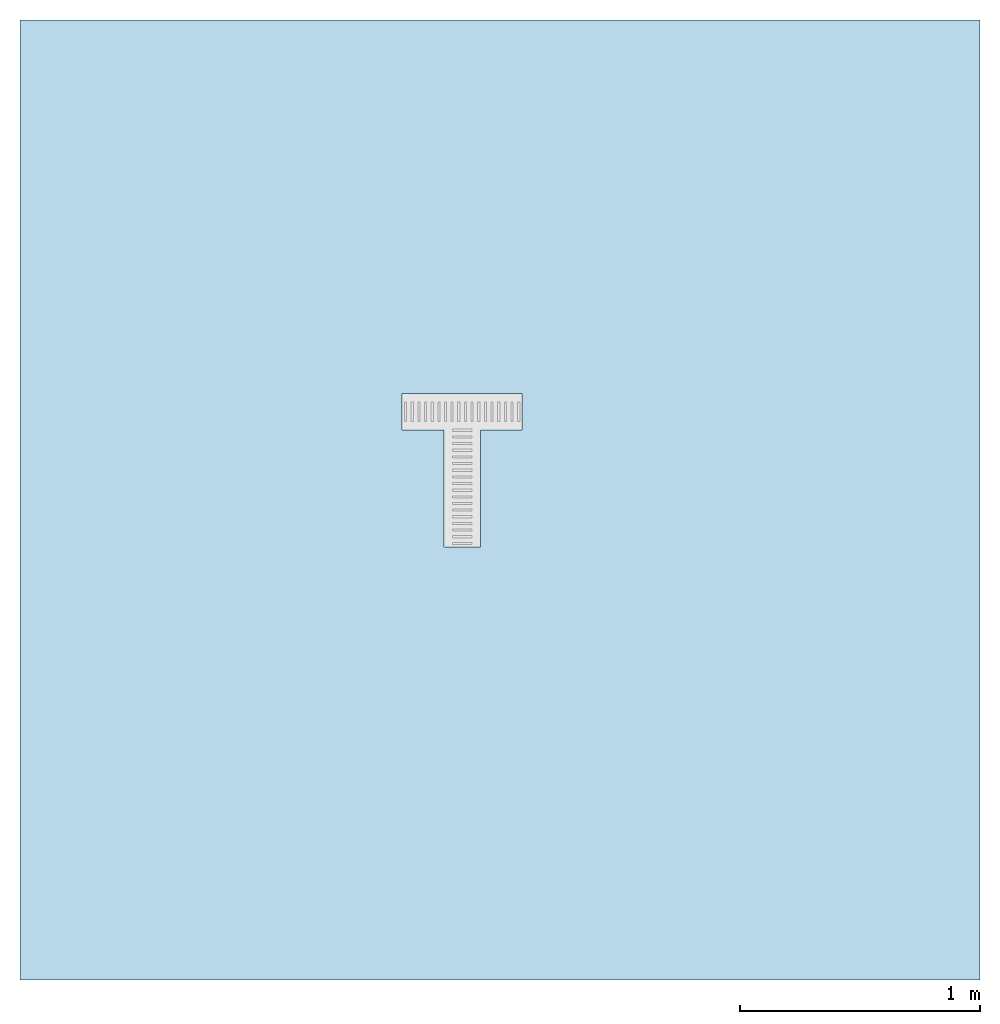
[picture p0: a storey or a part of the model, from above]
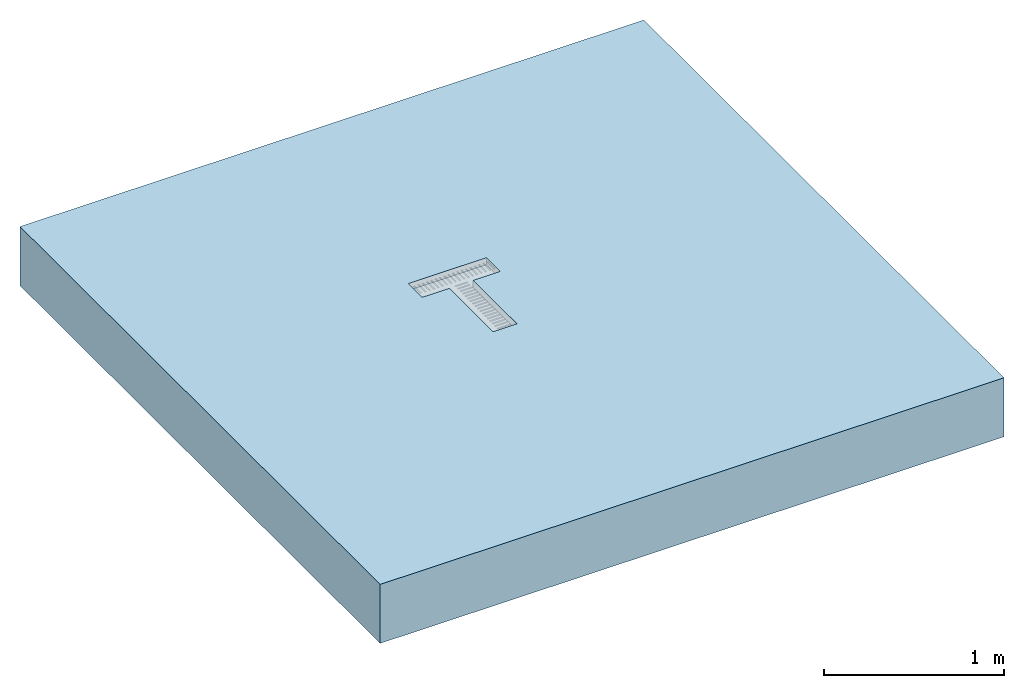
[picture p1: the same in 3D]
Properties of the parts of a building model (IFC2X3)

# File
Description: ViewDefinition [CoordinationView]
File name: 105261 - Level Invert Branch Unit.ifc
Time: 2014-03-20T14:31:36
Written by: Autodesk Revit 2013
Made in: 20120221_2030(x64)

# IfcProject, Project Number
LongName: Project Name; Phase: Project Status

# IfcSite, Default
RefLatitude: 42, 21, 30, 344238; RefLongitude: -71, -3, -35, -194702; RefElevation: 0 mm

# IfcBuilding
Pset_BuildingCommon - NumberOfStoreys: 1
Other - Project Issue Date: Issue Date; Project Name: Project Name; Client Name: Owner; Project Address: ## Street City, State Zip; Project Status: Project Status; Project Number: Project Number

# IfcBuildingStorey, Level 1
LongName: Level 1; Elevation: 0 mm
Constraints - Elevation Base: 0; Elevation: 0 mm
Graphics - Color: 0; Line Weight: 1; Symbol: M_Level Head - Circle: M_Level Head - Circle; Symbol at End 1 Default: no; Symbol at End 2 Default: yes; Line Pattern: Center
Identity Data - Building Story: yes; Structural: no; Name: Level 1
Dimensions - Computation Height: 0 mm

# IfcBuildingElementProxy: 105261 - Level Invert Branch Unit, ACO BD Deckline 125 Branch Unit:105261 - Level Invert Branch Unit:105261 - Level Invert Branch Unit:215225
In: Level 1
Material: Steel, Galvanized
Phasing - Phase Created: New Construction
Construction - End Plate Invert Flange: no; 105509 - C250 Perforated Grating - 500mm Long - Galvanized Finish.: no; 105523 - A15 Slotted Grating - 500mm Long - Galvanized Finish.: no; 15704 - C250 Composite Grating - 500mm Long - Black Coloured Finish.: no; End Plate Invert Web 2: no; 105525 - C250 Slotted Grating - 500mm Long - Galvanized Finish.: no; 10735 - C250 Composite Grating - 500mm Long - White Coloured Finish.: no; End Plate Invert Web 1: no; Grating: yes
Dimensions - Volume: 2593238 mm3
Constraints - Level: Level: Level 1; Moves With Nearby Elements: no
Pset_BuildingElementProxyCommon - Reference: 105261 - Level Invert Branch Unit
General - Product Description: ACO Deckline Level Invert Channel Branch; Product Code: 105261; Seal Colour: Black; Channel Recycled Material Content: 25 - 30 %; Seal Recyclable: Fully recyclable; Channel Colour: Galvanized; Product Range: ACO Deckline 125; Product Type: shallow invert surface water drainage system; Price: POA - contact ACO; Channel Material: Hot Dipped Galvanised Steel; Load Class: A15 - C250; Installation guidelines: X:\Electronic Literature\Building Drainage Literature\Deckline\Deckline 125.PDF; Weight (Kg): 3.9; Product Standard: BS EN 1433:2002, CE marked; NBS Specification: NBS Section Q10 Kerbs/edgings/channels/paving accessories, Clause 180 Drainage Channel Systems; Channel Recyclable: Fully recyclable; Maintenance guidelines: X:\Electronic Literature\Building Drainage Literature\Deckline\Deckline 125.PDF; Seal Material: Neoprene; Seal Recycled Material Content: 0%; Dimensions (LxWxH): 500 / 639mm x 153mm x 63mm
Identity Data - Cost: 0; Fax: +44 (0)1462 851490; Watermarked With: BIM Manager Premium Suite.; Watermarked By: www.acobd.com; Website: www.acobd.com; Manufacturer: ACO Building Drainage; Watermark2: This file is water marked and users are prohibited to reproduce, adapt, distribute this information.; E-mail Technical: abdtechnical@aco.co.uk; Address: ACO Business Centre, Caxton Road, Bedford, MK41 0LF; Telephone: +44 (0)1462 816666; Watermark1: This file is the property of ACO Technologies PLC; E-mail Sales: abdcommercial@aco.co.uk
Model Properties - Grating Product Code 15704: Load Class C250 - Composite Black - 500mm long - 1.2kg; Grating Product Code 105509: Load Class C250 - Perforated Galvanized Steel - 500mm long - 2.3kg; Grating Product Code 10735: Load Class C250 - Composite White - 500mm long - 1.2kg; Grating Product Code 105523: Load Class A15 - Slotted Galvanized Steel - 500mm long - 1.0kg; Grating Product Code 105525: Load Class C250 - Slotted Galvanized Steel - 500mm long - 2.3kg

# IfcOpeningElement: Recess
In: Level 1
Dimensions - Thickness: 400 mm; Perimeter: 16000 mm; Volume: 6392941099 mm3; Area: 16000000 mm2
Constraints - Related to Mass: no; Height Offset From Level: 0 mm; Room Bounding: yes; Level: Level: Level 1
Structural - Enable Analytical Model: no; Structural: no
Phasing - Phase Created: New Construction
Construction - Function: 0; Default Thickness: 400 mm
Analytical Properties - Roughness: 1; Heat Transfer Coefficient (U): 2.615; Absorptance: 0.1; Thermal Resistance (R): 0.382409; Thermal mass: 604440
Materials and Finishes - Structural Material: Concrete, Broom Finish
Graphics - Coarse Scale Fill Color: 0

# IfcSlab: Floor:Generic Floor - 400mm, Floor:Generic Floor - 400mm:193825
In: Level 1
PredefinedType: FLOOR; Material: Concrete, Broom Finish 400 mm
Dimensions - Thickness: 400 mm; Perimeter: 16000 mm; Volume: 6392941099 mm3; Area: 16000000 mm2
Constraints - Related to Mass: no; Height Offset From Level: 0 mm; Room Bounding: yes; Level: Level: Level 1
Structural - Enable Analytical Model: no; Structural: no
Phasing - Phase Created: New Construction
Pset_SlabCommon - Reference: Generic Floor - 400mm; IsExternal: no; LoadBearing: yes
Construction - Function: 0; Default Thickness: 400 mm
Analytical Properties - Roughness: 1; Heat Transfer Coefficient (U): 2.615; Absorptance: 0.1; Thermal Resistance (R): 0.382409; Thermal mass: 604440
Materials and Finishes - Structural Material: Concrete, Broom Finish
Graphics - Coarse Scale Fill Color: 0
